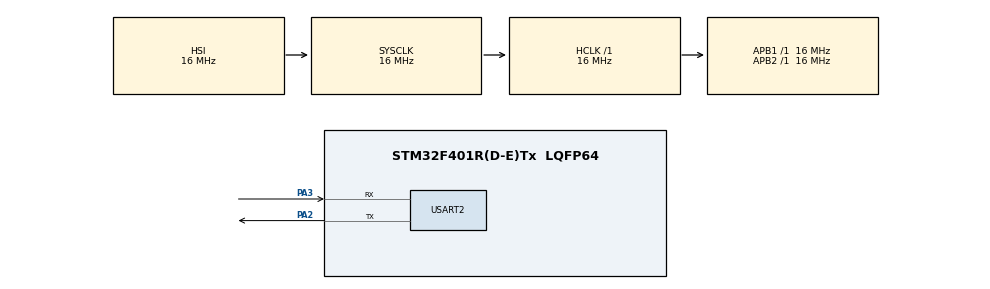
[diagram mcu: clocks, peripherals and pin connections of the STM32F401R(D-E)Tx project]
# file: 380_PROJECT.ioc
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Dma.Request0=USART2_RX
Dma.USART2_RX.0.Direction=DMA_PERIPH_TO_MEMORY
Dma.USART2_RX.0.FIFOMode=DMA_FIFOMODE_DISABLE
Dma.USART2_RX.0.Instance=DMA1_Stream5
Dma.USART2_RX.0.MemDataAlignment=DMA_MDATAALIGN_BYTE
Dma.USART2_RX.0.MemInc=DMA_MINC_ENABLE
Dma.USART2_RX.0.Mode=DMA_NORMAL
Dma.USART2_RX.0.PeriphDataAlignment=DMA_PDATAALIGN_BYTE
Dma.USART2_RX.0.PeriphInc=DMA_PINC_DISABLE
Dma.USART2_RX.0.Priority=DMA_PRIORITY_VERY_HIGH
Mcu.Family=STM32F4
Mcu.Name=STM32F401R(D-E)Tx
Mcu.Package=LQFP64
NVIC.DMA1_Stream5_IRQn=true\:0\:0\:false\:false\:true\:false\:true
NVIC.PriorityGroup=NVIC_PRIORITYGROUP_4
PA2.Mode=Asynchronous
PA2.Signal=USART2_TX
PA3.Mode=Asynchronous
PA3.Signal=USART2_RX
ProjectManager.HeapSize=0x200
ProjectManager.StackSize=0x400
ProjectManager.TargetToolchain=SW4STM32
RCC.AHBFreq_Value=16000000
RCC.APB1Freq_Value=16000000
RCC.APB2Freq_Value=16000000
RCC.CortexFreq_Value=16000000
RCC.HSE_VALUE=25000000
RCC.HSI_VALUE=16000000
RCC.LSE_VALUE=32768
RCC.SYSCLKFreq_VALUE=16000000
RCC.VCOOutputFreq_Value=192000000
USART2.VirtualMode=VM_ASYNC
board=custom

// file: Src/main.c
/* USER CODE BEGIN Header */
/**
  ******************************************************************************
  * @file           : main.c
  * @brief          : Main program body
  ******************************************************************************
  * @attention
  *
  * <h2><center>&copy; Copyright (c) 2019 STMicroelectronics.
  * All rights reserved.</center></h2>
  *
  * This software component is licensed by ST under BSD 3-Clause license,
  * the "License"; You may not use this file except in compliance with the
  * License. You may obtain a copy of the License at:
  *                        opensource.org/licenses/BSD-3-Clause
  *
  ******************************************************************************
  */
/* USER CODE END Header */

#include "main.h"
#include "structures.h"
#include "stm32f4xx.h"
//#include "stm32f4xx_nucleo.h"
//#include "stm32f4xx_hal_usart.h"
#include "stm32f4xx_hal_gpio.h"

#include "stm32f4xx_hal_def.h"
#include "stm32f4xx_hal.h"
#include <string.h>
#include <stdlib.h>

UART_HandleTypeDef huart2;
DMA_HandleTypeDef hdma_usart2_rx;
int speeds[6] = {0,0,0,0,0,0};
uint8_t rxBuf[8] = {0,0,0,0,0,0,0,0};
GPIO_TypeDef *PIN_GPIO[12] = {
                              GPIOA,
                              GPIOB,
                              GPIOB,
                              GPIOB,
                              GPIOB,
                              GPIOA,
                              GPIOA,
                              GPIOC,
                              GPIOB,
                              GPIOA,
                              GPIOA,
                              GPIOB
};

uint16_t PIN_NUM[12] = {
                    GPIO_PIN_10,
                    GPIO_PIN_3,
                    GPIO_PIN_5,
                    GPIO_PIN_4,
                    GPIO_PIN_10,
                    GPIO_PIN_8,
                    GPIO_PIN_9,
                    GPIO_PIN_7,
                    GPIO_PIN_6,
                    GPIO_PIN_7,
                    GPIO_PIN_6,
                    GPIO_PIN_9
};

int PIN_MOTORS[6][4] =  {
                          {0,1,2,3},
                          {4,5,6,7},
                          {8,9,10,11},
                          {1,0,3,2},
                          {5,4,7,6},
                          {9,8,11,10}
};

void SystemClock_Config(void);
static uint8_t MotorMsgParse(void);
static void MX_GPIO_Init(void);
static void MX_DMA_Init(void);
static void MX_USART2_UART_Init(void);
void HAL_UART_RxCpltCallback(UART_HandleTypeDef *huart);
static void SendString (char *msg);
static void Stop_Motor(int motorNum);
static void Run_Motor(int motorNum);
static void Run_Motor_Rev(int motorNum);
static void Spin_Motors(void);
static void LED_Command(int i);

/* USER CODE BEGIN 0 */
void HAL_UART_RxCpltCallback(UART_HandleTypeDef *huart){
  LED_Command(1);

  if(rxBuf[0] == LSB_CONNECT){
	  SendString("ACK");
	  SendString("ACK");
	  SendString("ACK");
  }
  rxBuf[7]=3;
}
/* USER CODE END 0 */

int main(void)
{

  /* MCU Configuration--------------------------------------------------------*/

  /* Reset of all peripherals, Initializes the Flash interface and the Systick. */
  HAL_Init();

  /* USER CODE BEGIN Init */
//  BSP_LED_Init(LED2);
  /* USER CODE END Init */

  /* Configure the system clock */
  SystemClock_Config();

  /* Initialize all configured peripherals */
  MX_GPIO_Init();
  MX_DMA_Init();
  MX_USART2_UART_Init();
  HAL_UART_Receive_DMA(&huart2,rxBuf,sizeof(rxBuf));
  /* Infinite loop */
  while (1)
  {
    LED_Command(0);
    if(rxBuf[0] == LSB_MOTOR){
      MotorMsgParse();
    }
    if(rxBuf[7]==3){
	    HAL_UART_Receive_DMA(&huart2,rxBuf,sizeof(rxBuf));
	    rxBuf[7]=1;
    }
  }
}

void SystemClock_Config(void)
{
  RCC_OscInitTypeDef RCC_OscInitStruct = {0};
  RCC_ClkInitTypeDef RCC_ClkInitStruct = {0};

  /** Configure the main internal regulator output voltage
  */
  __HAL_RCC_PWR_CLK_ENABLE();
  __HAL_PWR_VOLTAGESCALING_CONFIG(PWR_REGULATOR_VOLTAGE_SCALE2);
  /** Initializes the CPU, AHB and APB busses clocks
  */
  RCC_OscInitStruct.OscillatorType = RCC_OSCILLATORTYPE_HSI;
  RCC_OscInitStruct.HSIState = RCC_HSI_ON;
  RCC_OscInitStruct.HSICalibrationValue = RCC_HSICALIBRATION_DEFAULT;
  RCC_OscInitStruct.PLL.PLLState = RCC_PLL_NONE;
  if (HAL_RCC_OscConfig(&RCC_OscInitStruct) != HAL_OK)
  {
    Error_Handler();
  }
  /** Initializes the CPU, AHB and APB busses clocks
  */
  RCC_ClkInitStruct.ClockType = RCC_CLOCKTYPE_HCLK|RCC_CLOCKTYPE_SYSCLK
                              |RCC_CLOCKTYPE_PCLK1|RCC_CLOCKTYPE_PCLK2;
  RCC_ClkInitStruct.SYSCLKSource = RCC_SYSCLKSOURCE_HSI;
  RCC_ClkInitStruct.AHBCLKDivider = RCC_SYSCLK_DIV1;
  RCC_ClkInitStruct.APB1CLKDivider = RCC_HCLK_DIV1;
  RCC_ClkInitStruct.APB2CLKDivider = RCC_HCLK_DIV1;

  __GPIOA_CLK_ENABLE();
  __GPIOB_CLK_ENABLE();
  __GPIOC_CLK_ENABLE();

  if (HAL_RCC_ClockConfig(&RCC_ClkInitStruct, FLASH_LATENCY_0) != HAL_OK)
  {
    Error_Handler();
  }
}

static void MX_USART2_UART_Init(void)
{

  huart2.Instance = USART2;
  huart2.Init.BaudRate = 115200;
  huart2.Init.WordLength = UART_WORDLENGTH_8B;
  huart2.Init.StopBits = UART_STOPBITS_1;
  huart2.Init.Parity = UART_PARITY_NONE;
  huart2.Init.Mode = UART_MODE_TX_RX;
  huart2.Init.HwFlowCtl = UART_HWCONTROL_NONE;
  huart2.Init.OverSampling = UART_OVERSAMPLING_16;
  if (HAL_UART_Init(&huart2) != HAL_OK)
  {
    Error_Handler();
  }

}

static void MX_DMA_Init(void)
{

  /* DMA controller clock enable */
  __HAL_RCC_DMA1_CLK_ENABLE();

  /* DMA interrupt init */
  /* DMA1_Stream5_IRQn interrupt configuration */
  HAL_NVIC_SetPriority(DMA1_Stream5_IRQn, 0, 0);
  HAL_NVIC_EnableIRQ(DMA1_Stream5_IRQn);

}

static void MX_GPIO_Init(void)
{

  /* GPIO Ports Clock Enable */
  __HAL_RCC_GPIOC_CLK_ENABLE();
  __HAL_RCC_GPIOA_CLK_ENABLE();
  __HAL_RCC_GPIOB_CLK_ENABLE();

  GPIO_InitTypeDef GPIO_InitStruct = {0};
  //Init motor pins
  // GPIO A
  GPIO_InitStruct.Mode = GPIO_MODE_OUTPUT_PP;
  GPIO_InitStruct.Pull = GPIO_NOPULL;
  GPIO_InitStruct.Speed = GPIO_SPEED_FREQ_HIGH;
  GPIO_InitStruct.Pin = GPIO_PIN_10 | GPIO_PIN_9 | GPIO_PIN_8 | GPIO_PIN_7 | GPIO_PIN_6 | GPIO_PIN_5;
  HAL_GPIO_Init(GPIOA, &GPIO_InitStruct);
  // GPIO B
  GPIO_InitStruct.Mode = GPIO_MODE_OUTPUT_PP;
  GPIO_InitStruct.Pull = GPIO_NOPULL;
  GPIO_InitStruct.Speed = GPIO_SPEED_FREQ_HIGH;
  GPIO_InitStruct.Pin = GPIO_PIN_3 | GPIO_PIN_4 | GPIO_PIN_5 | GPIO_PIN_6 | GPIO_PIN_10 | GPIO_PIN_9;
  HAL_GPIO_Init(GPIOB, &GPIO_InitStruct);
  // GPIO C
  GPIO_InitStruct.Mode = GPIO_MODE_OUTPUT_PP;
  GPIO_InitStruct.Pull = GPIO_NOPULL;
  GPIO_InitStruct.Speed = GPIO_SPEED_FREQ_HIGH;
  GPIO_InitStruct.Pin = GPIO_PIN_7;
  HAL_GPIO_Init(GPIOC, &GPIO_InitStruct);
}

/* USER CODE BEGIN 4 */
static void LED_Command(int i){
  HAL_GPIO_WritePin(GPIOA,GPIO_PIN_5,i);
}
static void SendString (char *msg){
  while(HAL_UART_Transmit(&huart2,(uint8_t*)msg,strlen(msg),1000) != HAL_OK)
  {}
}

static void Stop_Motor(int motorNum){
  int i;
  for(i = 0; i<4; i++){
    HAL_GPIO_WritePin(PIN_GPIO[PIN_MOTORS[motorNum][i]],PIN_NUM[PIN_MOTORS[motorNum][i]],0);
  }
}

static void Run_Motor(int motorNum){
  int i;
  int j;
  for(i = 0; i<4; i++){
    for(j=0; j<4; j++){
      if(j==i){
        HAL_GPIO_WritePin(PIN_GPIO[PIN_MOTORS[motorNum][j]],PIN_NUM[PIN_MOTORS[motorNum][j]],1);
      }
      else{
        HAL_GPIO_WritePin(PIN_GPIO[PIN_MOTORS[motorNum][j]],PIN_NUM[PIN_MOTORS[motorNum][j]],0);
      }
    }
    HAL_Delay(MOTOR_DELAY);
  }
}

static void Run_Motor_Rev(int motorNum){
  int i;
  int j;
  for(i = 3; i>=0; i--){
    for(j=0; j<4; j++){
      if(j==i){
        HAL_GPIO_WritePin(PIN_GPIO[PIN_MOTORS[motorNum][j]],PIN_NUM[PIN_MOTORS[motorNum][j]],1);
      }
      else{
        HAL_GPIO_WritePin(PIN_GPIO[PIN_MOTORS[motorNum][j]],PIN_NUM[PIN_MOTORS[motorNum][j]],0);
      }
    }
    HAL_Delay(MOTOR_DELAY);
  }
}

static void Spin_Motors(void){
  int i;
  int j;
  // Loop only for max cycles
  for (i = 0; i<MAX_CYCLES_PER_STEP; i++){
    // Run each motor every cycle
    for (j = 0; j<6; j++){
      if (speeds[j] == 0){
          Stop_Motor(j);
      }
      else{
        if ((i+1)%abs(speeds[j]) == 0){
          if (speeds[j] > 0){
            Run_Motor(j);
          }
          else{
            Run_Motor_Rev(j);
          }
        }
      }
    }
    HAL_Delay(CYCLE_DELAY);
  }
}

static uint8_t MotorMsgParse(void){
  int i;
  // Convert speeds to cycles/step
  // 0 means no speed
  // 1-100 == 1-20 (same in negatives)
  // Looking at rxBuf[i+1] because first byte is LSB
  for (i = 0; i<6; i++){
    speeds[i] = 0;
  }
  // Iterate through motors
  for (i = 0; i<6; i++){
    // Get motor value for each motor (-20 -> 20 scale)
    if (rxBuf[i+1] == 0){
      speeds[i] = 0;
    }
    else{
      speeds[i] = (MAX_CYCLES_PER_STEP-1)*(1-(abs(rxBuf[i+1])-1)/(MAX_MOTOR_CMD-1)) + 1;
      speeds[i] = speeds[i] * abs(rxBuf[i+1]) / rxBuf[i+1]; //preserve sign
    }
  }
  Spin_Motors();
}
/* USER CODE END 4 */

void Error_Handler(void)
{
}

/************************ (C) COPYRIGHT STMicroelectronics *****END OF FILE****/
